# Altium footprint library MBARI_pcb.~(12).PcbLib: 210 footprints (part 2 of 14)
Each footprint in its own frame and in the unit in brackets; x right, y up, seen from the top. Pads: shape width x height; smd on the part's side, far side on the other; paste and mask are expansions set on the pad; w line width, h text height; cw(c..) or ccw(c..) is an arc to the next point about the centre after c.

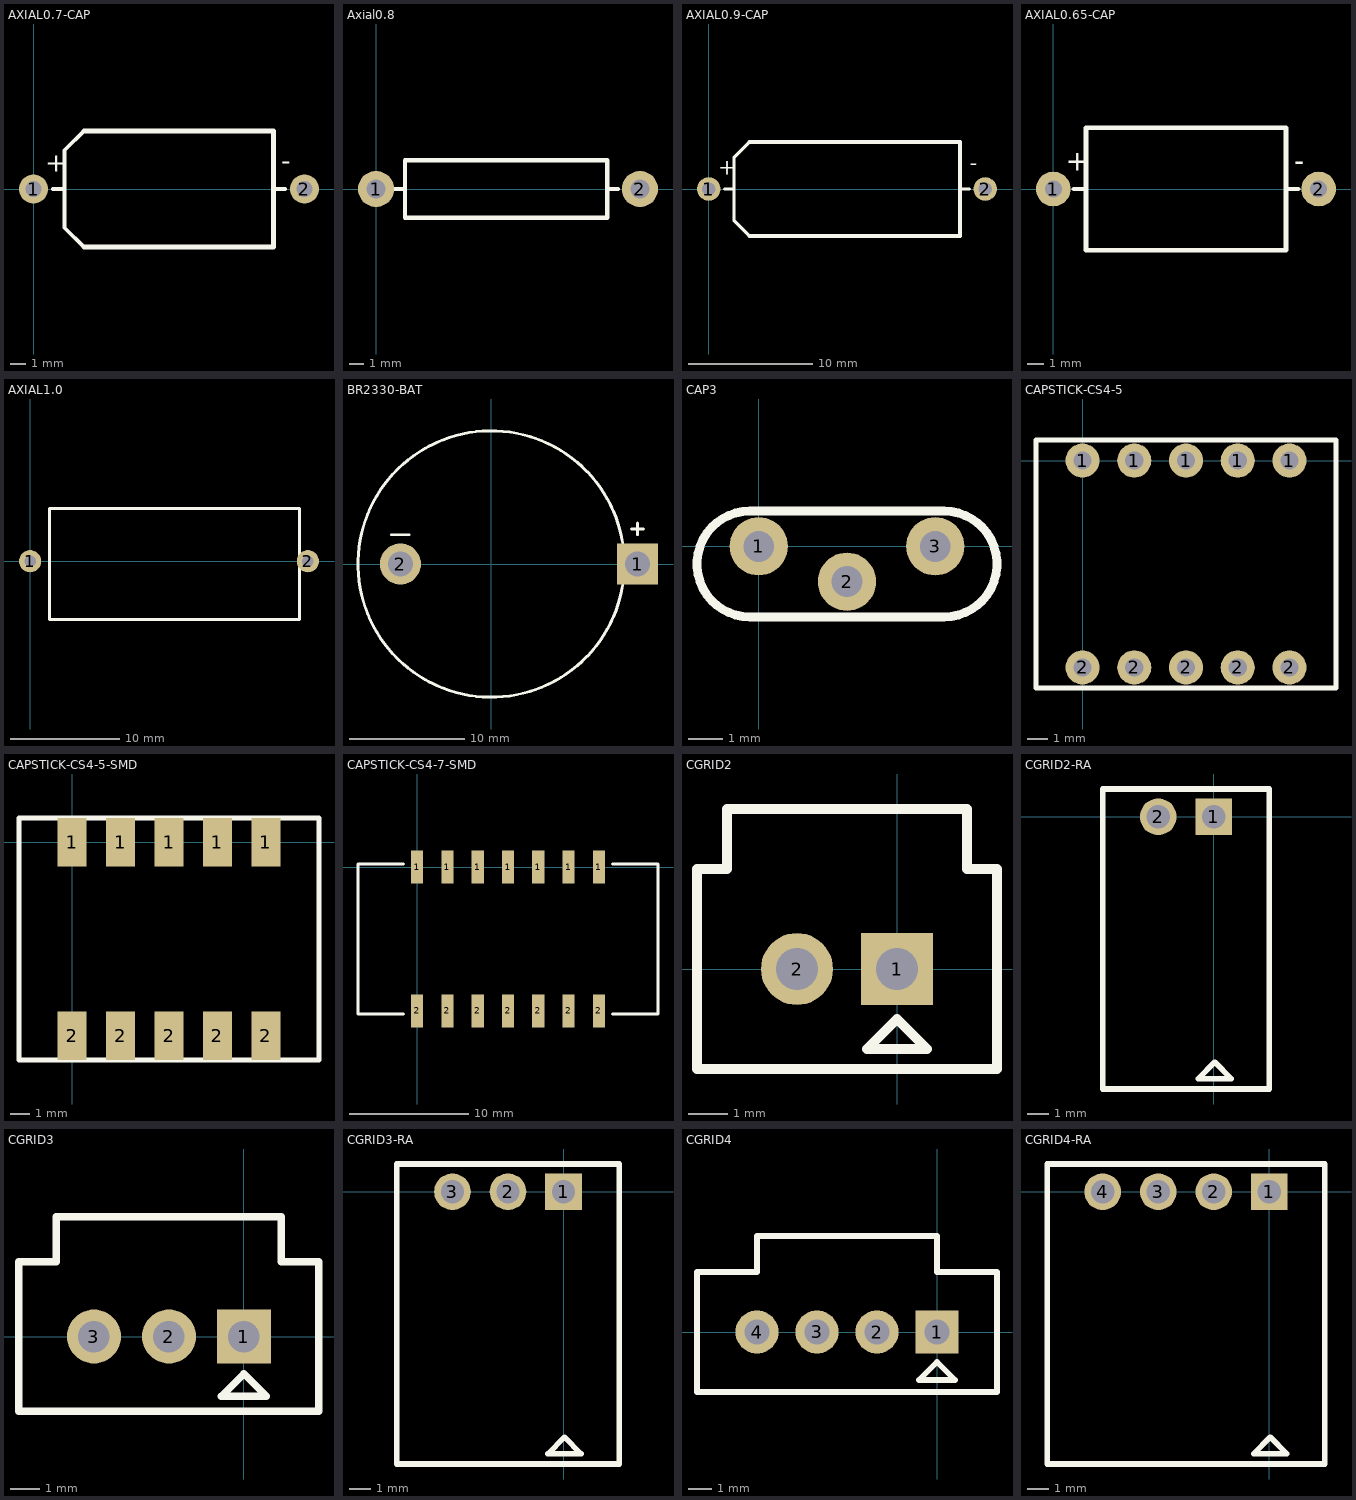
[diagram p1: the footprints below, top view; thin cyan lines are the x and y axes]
## AXIAL0.7-CAP [mil]
pads (2):
  round 75 hole 42: 1(0,0) 2(700,0)
TopOverlay:
  lines w10: 50,0 80,0 ; 130,-150 80,-100 80,0 ; 130,150 80,100 80,0 ; 620,0 650,0
  lines w12: 130,-150 620,-150 620,150 130,150
  text "+" at 30,45 h50
  text "-" at 640,50 h50

## Axial0.8 [mil]
pads (2):
  round 100 hole 52: 1(0,0) 2(730,0)
TopOverlay:
  lines w10: 50,0 80,0 ; 640,0 670,0
  lines w12: 80,-80 640,-80 640,80 80,80 80,-80

## AXIAL0.9-CAP [mil]
pads (2):
  round 75 hole 42: 1(0,0) 2(880,0)
TopOverlay:
  lines w10: 50,0 80,0 ; 130,-150 80,-100 80,0 ; 130,150 80,100 80,0 ; 800,0 830,0
  lines w12: 130,-150 800,-150 800,150 130,150
  text "-" at 830,60 h50
  text "+" at 30,45 h50

## AXIAL0.65-CAP [mil]
pads (2):
  round 85 hole 42: 1(0,0) 2(650,0)
TopOverlay:
  lines w10: 50,0 80,0 ; 570,0 600,0
  lines w12: 80,-150 570,-150 570,150 80,150 80,-150
  text "+" at 30,45 h50
  text "-" at 590,45 h50

## AXIAL1.0 [mil]
pads (2):
  round 80 hole 42: 1(0,0) 2(1000,0)
TopOverlay:
  lines w12: 70,-210 970,-210 970,190 70,190 70,-210

## BR2330-BAT [mil] "BR2330 lithium battery horiz mounted"
height 120
pads (2):
  rect 140x140 hole 86: 1(500,0)
  round 140 hole 86: 2(-310,0)
TopOverlay:
  circle w10: c0,0 r455
  lines w10: -340,100 -280,100 ; 480,120 500,120 520,120 ; 500,100 500,140

## CAP3 [mil]
pads (3):
  round 66 hole 35: 1(0,0) 2(100,-40) 3(200,0)
TopOverlay:
  lines w10: -10,-80 cw(c-10,-20) -10,40 210,40 cw(c210,-20) 210,-80 -10,-80

## CAPSTICK-CS4-5 [mil]
pads (10):
  round 66 hole 35: 1(0,0) 1(100,0) 1(200,0) 1(300,0) 1(400,0) 2(0,-400) 2(100,-400) 2(200,-400) 2(300,-400) 2(400,-400)
TopOverlay:
  lines w10: -90,-440 490,-440 490,40 -90,40 -90,-440

## CAPSTICK-CS4-5-SMD [mil]
pads (10):
  rect 60x100 smd: 1(0,0) 1(100,0) 1(200,0) 1(300,0) 1(400,0) 2(0,-400) 2(100,-400) 2(200,-400) 2(300,-400) 2(400,-400)
TopOverlay:
  lines w10: -110,-450 -110,50 510,50 510,-450 -110,-450

## CAPSTICK-CS4-7-SMD [mil] "Capstick CS4 case with 7 leads per side"
pads (14):
  rect 40x110 smd: 1(0,0) 1(100,0) 1(200,0) 1(300,0) 1(400,0) 1(500,0) 1(600,0) 2(0,-475) 2(100,-475) 2(200,-475) 2(300,-475) 2(400,-475) 2(500,-475) 2(600,-475)
TopOverlay:
  lines w10: -45,-485 -195,-485 -195,10 -45,10 ; 645,-485 795,-485 795,10 645,10

## CGRID2 [mil]
pads (2):
  rect 72x72 hole 42: 1(0,0)
  round 72 hole 42: 2(-100,0)
TopOverlay:
  lines w10: -200,-100 100,-100 100,100 70,100 70,160 -170,160 -170,100 -200,100 -200,-100 ; -30,-80 0,-50 30,-80 -30,-80

## CGRID2-RA [mil]
pads (2):
  rect 66x66 hole 42: 1(0,0)
  round 66 hole 42: 2(-100,0)
TopOverlay:
  lines w10: -200,-490 100,-490 100,50 -200,50 -200,-490 ; -28.29,-471.71 1.71,-441.71 31.71,-471.71 -28.29,-471.71

## CGRID3 [mil]
pads (3):
  rect 72x72 hole 42: 1(0,0)
  round 72 hole 42: 2(-100,0) 3(-200,0)
TopOverlay:
  lines w10: -300,-100 -300,100 -250,100 -250,160 50,160 50,100 100,100 100,-100 -300,-100 ; -30,-79.88 0,-49.88 30,-79.88 -30,-79.88

## CGRID3-RA [mil]
pads (3):
  rect 66x66 hole 42: 1(0,0)
  round 66 hole 42: 2(-100,0) 3(-200,0)
TopOverlay:
  lines w10: -300,-490 100,-490 100,50 -300,50 -300,-490 ; -28.29,-471.71 1.71,-441.71 31.71,-471.71 -28.29,-471.71

## CGRID4 [mil]
pads (4):
  rect 72x72 hole 42: 1(0,0)
  round 72 hole 42: 2(-100,0) 3(-200,0) 4(-300,0)
TopOverlay:
  lines w10: -400,-100 -400,100 -300,100 -300,160 0,160 0,100 100,100 100,-100 -400,-100 ; -30,-80 30,-80 0,-50 -30,-80

## CGRID4-RA [mil]
pads (4):
  rect 66x66 hole 42: 1(0,0)
  round 66 hole 42: 2(-100,0) 3(-200,0) 4(-300,0)
TopOverlay:
  lines w10: -400,-490 -400,50 100,50 100,-490 -400,-490 ; -28.29,-471.71 31.71,-471.71 1.71,-441.71 -28.29,-471.71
